VERSION 5.7 ;
BUSBITCHARS "[]" ;
DIVIDERCHAR "/" ;

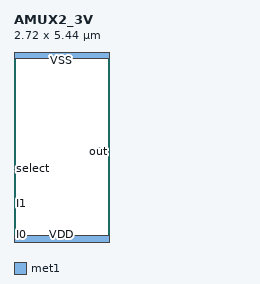
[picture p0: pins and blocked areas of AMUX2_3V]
MACRO AMUX2_3V
  CLASS BLOCK ;
  ORIGIN 0.000 0.000 ;
  FOREIGN AMUX2_3V 0.000 0.000 ;
  SIZE 2.720 BY 5.440 ;
  SYMMETRY X Y ;
  
  PIN VDD
    DIRECTION INOUT ;
    USE POWER ;
    SHAPE ABUTMENT ;
    PORT
      LAYER met1 ;
        RECT 0.000 0.000 2.720 0.200 ;
    END
  END VDD
  
  PIN VSS
    DIRECTION INOUT ;
    USE GROUND ;
    SHAPE ABUTMENT ;
    PORT
      LAYER met1 ;
        RECT 0.000 5.240 2.720 5.440 ;
    END
  END VSS
  
  PIN I0
    DIRECTION INPUT ;
    USE SIGNAL ;
    PORT
      LAYER met1 ;
        RECT 0.100 0.100 0.300 0.300 ;
    END
  END I0

  PIN I1
    DIRECTION INPUT ;
    USE SIGNAL ;
    PORT
      LAYER met1 ;
        RECT 0.100 1.000 0.300 1.200 ;
    END
  END I1

  PIN select
    DIRECTION INPUT ;
    USE SIGNAL ;
    PORT
      LAYER met1 ;
        RECT 0.100 2.000 0.300 2.200 ;
    END
  END select

  PIN out
    DIRECTION OUTPUT ;
    USE SIGNAL ;
    PORT
      LAYER met1 ;
        RECT 2.420 2.500 2.620 2.700 ;
    END
  END out

END AMUX2_3V

